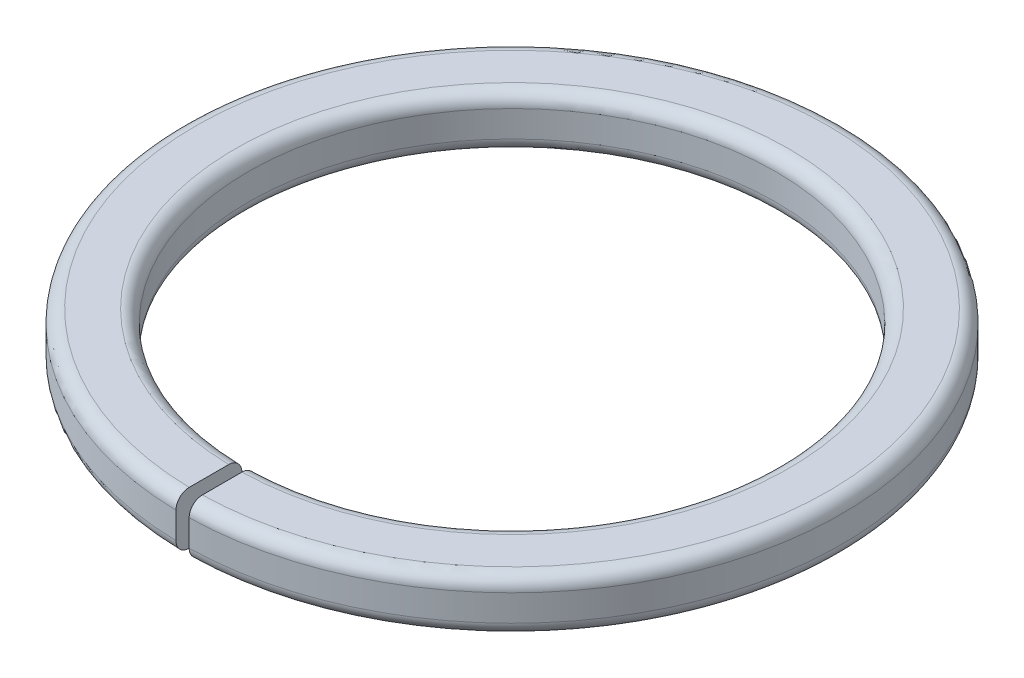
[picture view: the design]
ISO-10303-21;
HEADER;
FILE_DESCRIPTION(('STEP AP214'),'2;1');
FILE_NAME('part.step','',(''),(''),'','','');
FILE_SCHEMA(('AUTOMOTIVE_DESIGN { 1 0 10303 214 1 1 1 1 }'));
ENDSEC;
DATA;
#1=APPLICATION_CONTEXT('core data for automotive mechanical design processes');
#2=APPLICATION_PROTOCOL_DEFINITION('international standard','automotive_design',2000,#1);
#3=PRODUCT_CONTEXT('',#1,'mechanical');
#4=PRODUCT('Part','Part','',(#3));
#5=PRODUCT_RELATED_PRODUCT_CATEGORY('part','',(#4));
#6=PRODUCT_DEFINITION_FORMATION('','',#4);
#7=PRODUCT_DEFINITION_CONTEXT('part definition',#1,'design');
#8=PRODUCT_DEFINITION('design','',#6,#7);
#9=PRODUCT_DEFINITION_SHAPE('','',#8);
#10=(LENGTH_UNIT() NAMED_UNIT(*) SI_UNIT(.MILLI.,.METRE.));
#11=(NAMED_UNIT(*) PLANE_ANGLE_UNIT() SI_UNIT($,.RADIAN.));
#12=(NAMED_UNIT(*) SI_UNIT($,.STERADIAN.) SOLID_ANGLE_UNIT());
#13=UNCERTAINTY_MEASURE_WITH_UNIT(LENGTH_MEASURE(1.E-05),#10,'distance_accuracy_value','');
#14=(GEOMETRIC_REPRESENTATION_CONTEXT(3) GLOBAL_UNCERTAINTY_ASSIGNED_CONTEXT((#13)) GLOBAL_UNIT_ASSIGNED_CONTEXT((#10,
#11,#12)) REPRESENTATION_CONTEXT('',''));
#15=CARTESIAN_POINT('',(0.,0.,0.));
#16=DIRECTION('',(0.,0.,1.));
#17=DIRECTION('',(1.,0.,0.));
#18=AXIS2_PLACEMENT_3D('',#15,#16,#17);
#19=CARTESIAN_POINT('',(0.,0.8,0.));
#20=DIRECTION('',(0.,1.,0.));
#21=DIRECTION('',(0.,0.,1.));
#22=AXIS2_PLACEMENT_3D('',#19,#20,#21);
#23=PLANE('',#22);
#24=DIRECTION('',(0.,0.,1.));
#25=VECTOR('',#24,1.);
#26=CARTESIAN_POINT('',(-0.1,0.8,0.));
#27=LINE('',#26,#25);
#28=CARTESIAN_POINT('',(-0.1,0.8,4.1988093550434));
#29=VERTEX_POINT('',#28);
#30=CARTESIAN_POINT('',(-0.1,0.8,4.79895822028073));
#31=VERTEX_POINT('',#30);
#32=EDGE_CURVE('E48',#29,#31,#27,.T.);
#33=ORIENTED_EDGE('',*,*,#32,.F.);
#34=CARTESIAN_POINT('',(0.,0.8,0.));
#35=DIRECTION('',(0.,1.,0.));
#36=DIRECTION('',(0.,0.,1.));
#37=AXIS2_PLACEMENT_3D('',#34,#35,#36);
#38=CIRCLE('',#37,4.2);
#39=CARTESIAN_POINT('',(0.1,0.8,4.1988093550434));
#40=VERTEX_POINT('',#39);
#41=EDGE_CURVE('E110',#29,#40,#38,.F.);
#42=ORIENTED_EDGE('',*,*,#41,.T.);
#43=DIRECTION('',(0.,0.,-1.));
#44=VECTOR('',#43,1.);
#45=CARTESIAN_POINT('',(0.1,0.8,0.));
#46=LINE('',#45,#44);
#47=CARTESIAN_POINT('',(0.1,0.8,4.79895822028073));
#48=VERTEX_POINT('',#47);
#49=EDGE_CURVE('E113',#48,#40,#46,.T.);
#50=ORIENTED_EDGE('',*,*,#49,.F.);
#51=CARTESIAN_POINT('',(0.,0.8,0.));
#52=DIRECTION('',(0.,1.,0.));
#53=DIRECTION('',(0.,0.,1.));
#54=AXIS2_PLACEMENT_3D('',#51,#52,#53);
#55=CIRCLE('',#54,4.8);
#56=EDGE_CURVE('E112',#48,#31,#55,.T.);
#57=ORIENTED_EDGE('',*,*,#56,.T.);
#58=EDGE_LOOP('',(#33,#42,#50,#57));
#59=FACE_BOUND('',#58,.T.);
#60=ADVANCED_FACE('F30',(#59),#23,.T.);
#61=CARTESIAN_POINT('',(0.,0.,0.));
#62=DIRECTION('',(0.,1.,0.));
#63=DIRECTION('',(0.,0.,1.));
#64=AXIS2_PLACEMENT_3D('',#61,#62,#63);
#65=PLANE('',#64);
#66=CARTESIAN_POINT('',(0.,0.,0.));
#67=DIRECTION('',(0.,1.,0.));
#68=DIRECTION('',(0.,0.,1.));
#69=AXIS2_PLACEMENT_3D('',#66,#67,#68);
#70=CIRCLE('',#69,4.2);
#71=CARTESIAN_POINT('',(0.1,0.,4.1988093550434));
#72=VERTEX_POINT('',#71);
#73=CARTESIAN_POINT('',(-0.1,0.,4.1988093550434));
#74=VERTEX_POINT('',#73);
#75=EDGE_CURVE('E176',#72,#74,#70,.T.);
#76=ORIENTED_EDGE('',*,*,#75,.T.);
#77=DIRECTION('',(0.,0.,1.));
#78=VECTOR('',#77,1.);
#79=CARTESIAN_POINT('',(-0.1,0.,0.));
#80=LINE('',#79,#78);
#81=CARTESIAN_POINT('',(-0.1,-1.44818612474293E-11,4.79895822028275));
#82=VERTEX_POINT('',#81);
#83=EDGE_CURVE('E166',#74,#82,#80,.T.);
#84=ORIENTED_EDGE('',*,*,#83,.T.);
#85=CARTESIAN_POINT('',(0.,0.,0.));
#86=DIRECTION('',(0.,1.,0.));
#87=DIRECTION('',(0.,0.,1.));
#88=AXIS2_PLACEMENT_3D('',#85,#86,#87);
#89=CIRCLE('',#88,4.8);
#90=CARTESIAN_POINT('',(0.1,0.,4.79895822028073));
#91=VERTEX_POINT('',#90);
#92=EDGE_CURVE('E179',#82,#91,#89,.F.);
#93=ORIENTED_EDGE('',*,*,#92,.T.);
#94=DIRECTION('',(0.,0.,-1.));
#95=VECTOR('',#94,1.);
#96=CARTESIAN_POINT('',(0.1,0.,0.));
#97=LINE('',#96,#95);
#98=EDGE_CURVE('E150',#91,#72,#97,.T.);
#99=ORIENTED_EDGE('',*,*,#98,.T.);
#100=EDGE_LOOP('',(#76,#84,#93,#99));
#101=FACE_BOUND('',#100,.T.);
#102=ADVANCED_FACE('F194',(#101),#65,.F.);
#103=CARTESIAN_POINT('',(0.,0.8,0.));
#104=DIRECTION('',(0.,-1.,0.));
#105=DIRECTION('',(0.,0.,-1.));
#106=AXIS2_PLACEMENT_3D('',#103,#104,#105);
#107=CYLINDRICAL_SURFACE('',#106,5.);
#108=CARTESIAN_POINT('',(0.,0.2,0.));
#109=DIRECTION('',(0.,1.,0.));
#110=DIRECTION('',(0.,0.,1.));
#111=AXIS2_PLACEMENT_3D('',#108,#109,#110);
#112=CIRCLE('',#111,5.);
#113=CARTESIAN_POINT('',(0.1,0.2,4.99899989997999));
#114=VERTEX_POINT('',#113);
#115=CARTESIAN_POINT('',(-0.1,0.2,4.99899989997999));
#116=VERTEX_POINT('',#115);
#117=EDGE_CURVE('E173',#114,#116,#112,.T.);
#118=ORIENTED_EDGE('',*,*,#117,.T.);
#119=DIRECTION('',(0.,-1.,0.));
#120=VECTOR('',#119,1.);
#121=CARTESIAN_POINT('',(-0.1,0.8,4.99899989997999));
#122=LINE('',#121,#120);
#123=CARTESIAN_POINT('',(-0.1,0.6,4.99899989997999));
#124=VERTEX_POINT('',#123);
#125=EDGE_CURVE('E203',#116,#124,#122,.F.);
#126=ORIENTED_EDGE('',*,*,#125,.T.);
#127=CARTESIAN_POINT('',(0.,0.6,0.));
#128=DIRECTION('',(0.,1.,0.));
#129=DIRECTION('',(0.,0.,1.));
#130=AXIS2_PLACEMENT_3D('',#127,#128,#129);
#131=CIRCLE('',#130,5.);
#132=CARTESIAN_POINT('',(0.1,0.6,4.99899989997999));
#133=VERTEX_POINT('',#132);
#134=EDGE_CURVE('E104',#124,#133,#131,.F.);
#135=ORIENTED_EDGE('',*,*,#134,.T.);
#136=DIRECTION('',(0.,-1.,0.));
#137=VECTOR('',#136,1.);
#138=CARTESIAN_POINT('',(0.1,0.8,4.99899989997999));
#139=LINE('',#138,#137);
#140=EDGE_CURVE('E56',#133,#114,#139,.T.);
#141=ORIENTED_EDGE('',*,*,#140,.T.);
#142=EDGE_LOOP('',(#118,#126,#135,#141));
#143=FACE_BOUND('',#142,.T.);
#144=ADVANCED_FACE('F32',(#143),#107,.T.);
#145=CARTESIAN_POINT('',(0.,0.8,0.));
#146=DIRECTION('',(0.,-1.,0.));
#147=DIRECTION('',(0.,0.,-1.));
#148=AXIS2_PLACEMENT_3D('',#145,#146,#147);
#149=CYLINDRICAL_SURFACE('',#148,4.);
#150=DIRECTION('',(0.,-1.,0.));
#151=VECTOR('',#150,1.);
#152=CARTESIAN_POINT('',(-0.1,0.8,3.99874980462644));
#153=LINE('',#152,#151);
#154=CARTESIAN_POINT('',(-0.1,0.199999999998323,3.99874980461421));
#155=VERTEX_POINT('',#154);
#156=CARTESIAN_POINT('',(-0.1,0.6,3.99874980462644));
#157=VERTEX_POINT('',#156);
#158=EDGE_CURVE('E99',#155,#157,#153,.F.);
#159=ORIENTED_EDGE('',*,*,#158,.F.);
#160=CARTESIAN_POINT('',(0.,0.2,0.));
#161=DIRECTION('',(0.,1.,0.));
#162=DIRECTION('',(0.,0.,1.));
#163=AXIS2_PLACEMENT_3D('',#160,#161,#162);
#164=CIRCLE('',#163,4.);
#165=CARTESIAN_POINT('',(0.1,0.200000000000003,3.99874980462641));
#166=VERTEX_POINT('',#165);
#167=EDGE_CURVE('E119',#155,#166,#164,.F.);
#168=ORIENTED_EDGE('',*,*,#167,.T.);
#169=DIRECTION('',(0.,-1.,0.));
#170=VECTOR('',#169,1.);
#171=CARTESIAN_POINT('',(0.1,0.8,3.99874980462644));
#172=LINE('',#171,#170);
#173=CARTESIAN_POINT('',(0.1,0.6,3.99874980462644));
#174=VERTEX_POINT('',#173);
#175=EDGE_CURVE('E149',#174,#166,#172,.T.);
#176=ORIENTED_EDGE('',*,*,#175,.F.);
#177=CARTESIAN_POINT('',(0.,0.6,0.));
#178=DIRECTION('',(0.,1.,0.));
#179=DIRECTION('',(0.,0.,1.));
#180=AXIS2_PLACEMENT_3D('',#177,#178,#179);
#181=CIRCLE('',#180,4.);
#182=EDGE_CURVE('E182',#174,#157,#181,.T.);
#183=ORIENTED_EDGE('',*,*,#182,.T.);
#184=EDGE_LOOP('',(#159,#168,#176,#183));
#185=FACE_BOUND('',#184,.T.);
#186=ADVANCED_FACE('F187',(#185),#149,.F.);
#187=CARTESIAN_POINT('',(0.,0.2,0.));
#188=DIRECTION('',(0.,1.,0.));
#189=DIRECTION('',(0.,0.,1.));
#190=AXIS2_PLACEMENT_3D('',#187,#188,#189);
#191=TOROIDAL_SURFACE('',#190,4.8,0.2);
#192=CARTESIAN_POINT('',(-0.1,0.106676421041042,4.62202654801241));
#193=CARTESIAN_POINT('',(-0.1,0.116610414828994,4.61678496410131));
#194=CARTESIAN_POINT('',(-0.1,0.126994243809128,4.6123783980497));
#195=CARTESIAN_POINT('',(-0.1,0.148363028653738,4.60536767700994));
#196=CARTESIAN_POINT('',(-0.1,0.159348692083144,4.60276569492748));
#197=CARTESIAN_POINT('',(-0.1,0.181596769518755,4.59944448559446));
#198=CARTESIAN_POINT('',(-0.1,0.192859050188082,4.5987243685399));
#199=CARTESIAN_POINT('',(-0.1,0.215341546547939,4.59918555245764));
#200=CARTESIAN_POINT('',(-0.1,0.226561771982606,4.60036638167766));
#201=CARTESIAN_POINT('',(-0.1,0.248645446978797,4.60459490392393));
#202=CARTESIAN_POINT('',(-0.1,0.259508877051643,4.60764269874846));
#203=CARTESIAN_POINT('',(-0.1,0.280570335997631,4.61551882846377));
#204=CARTESIAN_POINT('',(-0.1,0.290768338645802,4.62034723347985));
#205=CARTESIAN_POINT('',(-0.1,0.310209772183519,4.63164771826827));
#206=CARTESIAN_POINT('',(-0.1,0.319453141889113,4.63811990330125));
#207=CARTESIAN_POINT('',(-0.1,0.336722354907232,4.65252394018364));
#208=CARTESIAN_POINT('',(-0.1,0.344748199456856,4.6604557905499));
#209=CARTESIAN_POINT('',(-0.1,0.359356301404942,4.677555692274));
#210=CARTESIAN_POINT('',(-0.1,0.365938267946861,4.68672399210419));
#211=CARTESIAN_POINT('',(-0.1,0.37746994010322,4.7060352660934));
#212=CARTESIAN_POINT('',(-0.1,0.382419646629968,4.71617823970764));
#213=CARTESIAN_POINT('',(-0.1,0.390547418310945,4.73715334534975));
#214=CARTESIAN_POINT('',(-0.1,0.393725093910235,4.7479856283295));
#215=CARTESIAN_POINT('',(-0.1,0.398217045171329,4.77002991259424));
#216=CARTESIAN_POINT('',(-0.1,0.3995313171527,4.78124191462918));
#217=CARTESIAN_POINT('',(-0.1,0.400259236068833,4.80372900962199));
#218=CARTESIAN_POINT('',(-0.1,0.399672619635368,4.81500411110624));
#219=CARTESIAN_POINT('',(-0.1,0.396614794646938,4.83729579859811));
#220=CARTESIAN_POINT('',(-0.1,0.394143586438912,4.84831238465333));
#221=CARTESIAN_POINT('',(-0.1,0.387386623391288,4.86977430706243));
#222=CARTESIAN_POINT('',(-0.1,0.383100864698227,4.88021964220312));
#223=CARTESIAN_POINT('',(-0.1,0.372836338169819,4.90024241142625));
#224=CARTESIAN_POINT('',(-0.1,0.366857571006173,4.90981984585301));
#225=CARTESIAN_POINT('',(-0.1,0.353377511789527,4.92783359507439));
#226=CARTESIAN_POINT('',(-0.1,0.34587641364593,4.93627005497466));
#227=CARTESIAN_POINT('',(-0.1,0.329564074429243,4.95176359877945));
#228=CARTESIAN_POINT('',(-0.1,0.320752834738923,4.9588206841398));
#229=CARTESIAN_POINT('',(-0.1,0.302072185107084,4.97135367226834));
#230=CARTESIAN_POINT('',(-0.1,0.29220298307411,4.97682988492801));
#231=CARTESIAN_POINT('',(-0.1,0.271685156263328,4.98604733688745));
#232=CARTESIAN_POINT('',(-0.1,0.261036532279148,4.98978857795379));
#233=CARTESIAN_POINT('',(-0.1,0.239264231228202,4.99542921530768));
#234=CARTESIAN_POINT('',(-0.1,0.228140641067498,4.99732894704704));
#235=CARTESIAN_POINT('',(-0.1,0.205732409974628,4.999233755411));
#236=CARTESIAN_POINT('',(-0.1,0.194447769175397,4.9992388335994));
#237=CARTESIAN_POINT('',(-0.1,0.172038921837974,4.99735428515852));
#238=CARTESIAN_POINT('',(-0.1,0.160914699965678,4.99546484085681));
#239=CARTESIAN_POINT('',(-0.1,0.139141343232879,4.98984521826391));
#240=CARTESIAN_POINT('',(-0.1,0.128492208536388,4.98611503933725));
#241=CARTESIAN_POINT('',(-0.1,0.107970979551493,4.97691981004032));
#242=CARTESIAN_POINT('',(-0.1,0.0980989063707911,4.97145471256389));
#243=CARTESIAN_POINT('',(-0.1,0.0794122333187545,4.95894493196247));
#244=CARTESIAN_POINT('',(-0.1,0.0705976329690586,4.95190024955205));
#245=CARTESIAN_POINT('',(-0.1,0.0542747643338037,4.93643026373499));
#246=CARTESIAN_POINT('',(-0.1,0.0467666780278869,4.92800476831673));
#247=CARTESIAN_POINT('',(-0.1,0.0332712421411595,4.91001306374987));
#248=CARTESIAN_POINT('',(-0.1,0.0272838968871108,4.90044685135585));
#249=CARTESIAN_POINT('',(-0.1,0.0169986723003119,4.88044327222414));
#250=CARTESIAN_POINT('',(-0.1,0.0127011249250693,4.87000573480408));
#251=CARTESIAN_POINT('',(-0.1,0.0059189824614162,4.84855736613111));
#252=CARTESIAN_POINT('',(-0.1,0.00343439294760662,4.83754653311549));
#253=CARTESIAN_POINT('',(-0.1,0.00034827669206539,4.81526186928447));
#254=CARTESIAN_POINT('',(-0.1,-0.000252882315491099,4.80398798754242));
#255=CARTESIAN_POINT('',(-0.1,0.000445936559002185,4.78149972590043));
#256=CARTESIAN_POINT('',(-0.1,0.0017458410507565,4.7702853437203));
#257=CARTESIAN_POINT('',(-0.1,0.00620964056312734,4.74823428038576));
#258=CARTESIAN_POINT('',(-0.1,0.00937348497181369,4.7373975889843));
#259=CARTESIAN_POINT('',(-0.1,0.0174767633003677,4.71640634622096));
#260=CARTESIAN_POINT('',(-0.1,0.022416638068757,4.7062519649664));
#261=CARTESIAN_POINT('',(-0.1,0.033932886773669,4.68691354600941));
#262=CARTESIAN_POINT('',(-0.1,0.0405099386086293,4.67772991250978));
#263=CARTESIAN_POINT('',(-0.1,0.0551084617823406,4.66060628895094));
#264=CARTESIAN_POINT('',(-0.1,0.0631281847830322,4.65266481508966));
#265=CARTESIAN_POINT('',(-0.1,0.0771400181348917,4.64095160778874));
#266=CARTESIAN_POINT('',(-0.1,0.0827649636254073,4.63673287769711));
#267=CARTESIAN_POINT('',(-0.1,0.0944267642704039,4.62890941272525));
#268=CARTESIAN_POINT('',(-0.1,0.100463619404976,4.62530467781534));
#269=CARTESIAN_POINT('',(-0.1,0.106676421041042,4.62202654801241));
#270=B_SPLINE_CURVE_WITH_KNOTS('',3,(#192,#193,#194,#195,#196,#197,#198,#199,#200,#201,#202,
#203,#204,#205,#206,#207,#208,#209,#210,#211,#212,#213,#214,#215,#216,#217,#218,#219,#220,#221,
#222,#223,#224,#225,#226,#227,#228,#229,#230,#231,#232,#233,#234,#235,#236,#237,#238,#239,#240,
#241,#242,#243,#244,#245,#246,#247,#248,#249,#250,#251,#252,#253,#254,#255,#256,#257,#258,#259,
#260,#261,#262,#263,#264,#265,#266,#267,#268,#269),.UNSPECIFIED.,.T.,.F.,(4,2,2,2,2,2,2,2,2,2,2,
2,2,2,2,2,2,2,2,2,2,2,2,2,2,2,2,2,2,2,2,2,2,2,2,2,2,2,4),(0.,0.0336704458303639,
0.0673813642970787,0.101076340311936,0.13476295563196,0.168451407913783,0.202141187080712,
0.235833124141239,0.269525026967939,0.30322371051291,0.336922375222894,0.370628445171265,
0.404334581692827,0.438045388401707,0.471756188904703,0.505467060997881,0.539177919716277,
0.572884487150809,0.606591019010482,0.640290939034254,0.673990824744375,0.707684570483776,
0.741378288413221,0.775068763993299,0.808759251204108,0.842450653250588,0.876142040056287,
0.909838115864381,0.943534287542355,0.977237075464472,1.01093996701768,1.04464943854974,
1.07835760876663,1.11206486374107,1.14578049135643,1.17951010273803,1.21319911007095,
1.23425688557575,1.25531466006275),.UNSPECIFIED.);
#271=EDGE_CURVE('E205',#116,#82,#270,.T.);
#272=ORIENTED_EDGE('',*,*,#271,.F.);
#273=ORIENTED_EDGE('',*,*,#117,.F.);
#274=CARTESIAN_POINT('',(0.1,0.106676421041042,4.62202654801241));
#275=CARTESIAN_POINT('',(0.1,0.0967401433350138,4.62727046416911));
#276=CARTESIAN_POINT('',(0.1,0.0872395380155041,4.63335746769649));
#277=CARTESIAN_POINT('',(0.1,0.0693874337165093,4.64704547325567));
#278=CARTESIAN_POINT('',(0.1,0.0610373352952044,4.65464829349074));
#279=CARTESIAN_POINT('',(0.1,0.0457356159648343,4.67114505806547));
#280=CARTESIAN_POINT('',(0.1,0.0387833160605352,4.68003837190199));
#281=CARTESIAN_POINT('',(0.1,0.0264721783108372,4.69886340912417));
#282=CARTESIAN_POINT('',(0.1,0.021112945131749,4.70879487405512));
#283=CARTESIAN_POINT('',(0.1,0.0121359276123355,4.72941913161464));
#284=CARTESIAN_POINT('',(0.1,0.00851860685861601,4.74011212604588));
#285=CARTESIAN_POINT('',(0.1,0.00313007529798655,4.76195400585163));
#286=CARTESIAN_POINT('',(0.1,0.00135893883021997,4.77310290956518));
#287=CARTESIAN_POINT('',(0.1,-0.000286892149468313,4.79554134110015));
#288=CARTESIAN_POINT('',(0.1,-0.000161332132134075,4.80683088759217));
#289=CARTESIAN_POINT('',(0.1,0.00198331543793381,4.82922865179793));
#290=CARTESIAN_POINT('',(0.1,0.00400239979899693,4.84033686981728));
#291=CARTESIAN_POINT('',(0.1,0.00987692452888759,4.8620568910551));
#292=CARTESIAN_POINT('',(0.1,0.0137324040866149,4.87266868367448));
#293=CARTESIAN_POINT('',(0.1,0.0231703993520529,4.89309424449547));
#294=CARTESIAN_POINT('',(0.1,0.0287529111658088,4.90290801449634));
#295=CARTESIAN_POINT('',(0.1,0.0414858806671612,4.92145773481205));
#296=CARTESIAN_POINT('',(0.1,0.0486361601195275,4.9301938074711));
#297=CARTESIAN_POINT('',(0.1,0.0643021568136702,4.94634124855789));
#298=CARTESIAN_POINT('',(0.1,0.072817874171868,4.95375261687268));
#299=CARTESIAN_POINT('',(0.1,0.090971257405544,4.96703872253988));
#300=CARTESIAN_POINT('',(0.1,0.100608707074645,4.97291375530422));
#301=CARTESIAN_POINT('',(0.1,0.120733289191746,4.98296208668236));
#302=CARTESIAN_POINT('',(0.1,0.13122042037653,4.98713538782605));
#303=CARTESIAN_POINT('',(0.1,0.152744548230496,4.9936610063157));
#304=CARTESIAN_POINT('',(0.1,0.163781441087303,4.99601366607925));
#305=CARTESIAN_POINT('',(0.1,0.186093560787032,4.99883243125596));
#306=CARTESIAN_POINT('',(0.1,0.197368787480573,4.99929853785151));
#307=CARTESIAN_POINT('',(0.1,0.219836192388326,4.99833100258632));
#308=CARTESIAN_POINT('',(0.1,0.231028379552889,4.99689756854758));
#309=CARTESIAN_POINT('',(0.1,0.253013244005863,4.99217205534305));
#310=CARTESIAN_POINT('',(0.1,0.26380592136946,4.98887997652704));
#311=CARTESIAN_POINT('',(0.1,0.284685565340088,4.98053067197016));
#312=CARTESIAN_POINT('',(0.1,0.294772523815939,4.97547342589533));
#313=CARTESIAN_POINT('',(0.1,0.313954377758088,4.96373746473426));
#314=CARTESIAN_POINT('',(0.1,0.323049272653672,4.95705874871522));
#315=CARTESIAN_POINT('',(0.1,0.33999010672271,4.9422685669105));
#316=CARTESIAN_POINT('',(0.1,0.347835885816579,4.9341569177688));
#317=CARTESIAN_POINT('',(0.1,0.362054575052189,4.9167317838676));
#318=CARTESIAN_POINT('',(0.1,0.368427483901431,4.90741829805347));
#319=CARTESIAN_POINT('',(0.1,0.379520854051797,4.88785193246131));
#320=CARTESIAN_POINT('',(0.1,0.384240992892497,4.8775988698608));
#321=CARTESIAN_POINT('',(0.1,0.391893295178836,4.8564459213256));
#322=CARTESIAN_POINT('',(0.1,0.394825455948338,4.84554603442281));
#323=CARTESIAN_POINT('',(0.1,0.398819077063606,4.82340670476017));
#324=CARTESIAN_POINT('',(0.1,0.399880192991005,4.8121671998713));
#325=CARTESIAN_POINT('',(0.1,0.400100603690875,4.78966956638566));
#326=CARTESIAN_POINT('',(0.1,0.399259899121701,4.77841143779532));
#327=CARTESIAN_POINT('',(0.1,0.395700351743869,4.75619503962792));
#328=CARTESIAN_POINT('',(0.1,0.392981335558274,4.74523679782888));
#329=CARTESIAN_POINT('',(0.1,0.385742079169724,4.72393234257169));
#330=CARTESIAN_POINT('',(0.1,0.381221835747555,4.71358613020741));
#331=CARTESIAN_POINT('',(0.1,0.370508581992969,4.69380002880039));
#332=CARTESIAN_POINT('',(0.1,0.364315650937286,4.68436009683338));
#333=CARTESIAN_POINT('',(0.1,0.350432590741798,4.66665413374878));
#334=CARTESIAN_POINT('',(0.1,0.34274245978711,4.65838810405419));
#335=CARTESIAN_POINT('',(0.1,0.326084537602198,4.64326603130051));
#336=CARTESIAN_POINT('',(0.1,0.317116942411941,4.63640977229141));
#337=CARTESIAN_POINT('',(0.1,0.298158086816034,4.62430078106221));
#338=CARTESIAN_POINT('',(0.1,0.288166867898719,4.61904798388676));
#339=CARTESIAN_POINT('',(0.1,0.267447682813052,4.61029631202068));
#340=CARTESIAN_POINT('',(0.1,0.256719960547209,4.60679685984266));
#341=CARTESIAN_POINT('',(0.1,0.23482624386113,4.60164825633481));
#342=CARTESIAN_POINT('',(0.1,0.223660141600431,4.59999956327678));
#343=CARTESIAN_POINT('',(0.1,0.201207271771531,4.59860018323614));
#344=CARTESIAN_POINT('',(0.1,0.189920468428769,4.59885007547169));
#345=CARTESIAN_POINT('',(0.1,0.167558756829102,4.60124273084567));
#346=CARTESIAN_POINT('',(0.1,0.156483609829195,4.6033832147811));
#347=CARTESIAN_POINT('',(0.1,0.138922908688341,4.60833990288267));
#348=CARTESIAN_POINT('',(0.1,0.132275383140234,4.61060067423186));
#349=CARTESIAN_POINT('',(0.1,0.119254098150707,4.61580692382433));
#350=CARTESIAN_POINT('',(0.1,0.112880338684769,4.6187524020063));
#351=CARTESIAN_POINT('',(0.1,0.106676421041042,4.62202654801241));
#352=B_SPLINE_CURVE_WITH_KNOTS('',3,(#274,#275,#276,#277,#278,#279,#280,#281,#282,#283,#284,
#285,#286,#287,#288,#289,#290,#291,#292,#293,#294,#295,#296,#297,#298,#299,#300,#301,#302,#303,
#304,#305,#306,#307,#308,#309,#310,#311,#312,#313,#314,#315,#316,#317,#318,#319,#320,#321,#322,
#323,#324,#325,#326,#327,#328,#329,#330,#331,#332,#333,#334,#335,#336,#337,#338,#339,#340,#341,
#342,#343,#344,#345,#346,#347,#348,#349,#350,#351),.UNSPECIFIED.,.T.,.F.,(4,2,2,2,2,2,2,2,2,2,2,
2,2,2,2,2,2,2,2,2,2,2,2,2,2,2,2,2,2,2,2,2,2,2,2,2,2,2,4),(0.,0.0336797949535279,
0.0674002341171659,0.101104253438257,0.134799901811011,0.168504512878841,0.202210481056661,
0.235920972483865,0.26963140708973,0.303342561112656,0.337053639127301,0.370760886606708,
0.404468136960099,0.438168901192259,0.471869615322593,0.505563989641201,0.539258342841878,
0.57294900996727,0.60663967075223,0.640330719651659,0.674021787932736,0.707717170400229,
0.741412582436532,0.775114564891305,0.80881659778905,0.842524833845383,0.876233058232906,
0.909944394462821,0.943655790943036,0.977365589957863,1.01107542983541,1.04478010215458,
1.07848340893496,1.11217560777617,1.14587614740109,1.17958696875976,1.21325720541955,
1.23428587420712,1.25531454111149),.UNSPECIFIED.);
#353=EDGE_CURVE('E137',#91,#114,#352,.T.);
#354=ORIENTED_EDGE('',*,*,#353,.F.);
#355=ORIENTED_EDGE('',*,*,#92,.F.);
#356=EDGE_LOOP('',(#272,#273,#354,#355));
#357=FACE_BOUND('',#356,.T.);
#358=ADVANCED_FACE('F154',(#357),#191,.T.);
#359=CARTESIAN_POINT('',(0.,0.2,0.));
#360=DIRECTION('',(0.,1.,0.));
#361=DIRECTION('',(0.,0.,1.));
#362=AXIS2_PLACEMENT_3D('',#359,#360,#361);
#363=TOROIDAL_SURFACE('',#362,4.2,0.2);
#364=CARTESIAN_POINT('',(-0.1,0.108972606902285,4.0206723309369));
#365=CARTESIAN_POINT('',(-0.1,0.118972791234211,4.01555973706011));
#366=CARTESIAN_POINT('',(-0.1,0.129411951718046,4.01128782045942));
#367=CARTESIAN_POINT('',(-0.1,0.150868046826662,4.00455388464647));
#368=CARTESIAN_POINT('',(-0.1,0.161885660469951,4.00209404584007));
#369=CARTESIAN_POINT('',(-0.1,0.18417331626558,3.9990604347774));
#370=CARTESIAN_POINT('',(-0.1,0.195443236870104,3.99848577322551));
#371=CARTESIAN_POINT('',(-0.1,0.217916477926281,3.99923707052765));
#372=CARTESIAN_POINT('',(-0.1,0.229119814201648,4.00056255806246));
#373=CARTESIAN_POINT('',(-0.1,0.251145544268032,4.00507549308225));
#374=CARTESIAN_POINT('',(-0.1,0.261967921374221,4.00826302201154));
#375=CARTESIAN_POINT('',(-0.1,0.282924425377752,4.01640968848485));
#376=CARTESIAN_POINT('',(-0.1,0.293058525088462,4.02136889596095));
#377=CARTESIAN_POINT('',(-0.1,0.312351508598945,4.03291850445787));
#378=CARTESIAN_POINT('',(-0.1,0.321510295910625,4.03950906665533));
#379=CARTESIAN_POINT('',(-0.1,0.338591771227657,4.05413388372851));
#380=CARTESIAN_POINT('',(-0.1,0.346514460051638,4.06216813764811));
#381=CARTESIAN_POINT('',(-0.1,0.360901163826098,4.07945457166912));
#382=CARTESIAN_POINT('',(-0.1,0.36736478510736,4.0887070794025));
#383=CARTESIAN_POINT('',(-0.1,0.37864743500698,4.10816565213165));
#384=CARTESIAN_POINT('',(-0.1,0.383466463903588,4.11837171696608));
#385=CARTESIAN_POINT('',(-0.1,0.391324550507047,4.13945084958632));
#386=CARTESIAN_POINT('',(-0.1,0.39436309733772,4.15032410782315));
#387=CARTESIAN_POINT('',(-0.1,0.398571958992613,4.17242640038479));
#388=CARTESIAN_POINT('',(-0.1,0.399742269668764,4.18365543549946));
#389=CARTESIAN_POINT('',(-0.1,0.400181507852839,4.20615259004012));
#390=CARTESIAN_POINT('',(-0.1,0.39945010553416,4.2174207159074));
#391=CARTESIAN_POINT('',(-0.1,0.396105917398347,4.23967424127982));
#392=CARTESIAN_POINT('',(-0.1,0.393493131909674,4.25065964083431));
#393=CARTESIAN_POINT('',(-0.1,0.386460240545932,4.27203573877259));
#394=CARTESIAN_POINT('',(-0.1,0.382040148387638,4.28242644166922));
#395=CARTESIAN_POINT('',(-0.1,0.37151795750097,4.30231811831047));
#396=CARTESIAN_POINT('',(-0.1,0.365415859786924,4.31181909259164));
#397=CARTESIAN_POINT('',(-0.1,0.351703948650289,4.32965979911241));
#398=CARTESIAN_POINT('',(-0.1,0.344094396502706,4.33799973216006));
#399=CARTESIAN_POINT('',(-0.1,0.327582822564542,4.35328328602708));
#400=CARTESIAN_POINT('',(-0.1,0.318680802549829,4.36022690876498));
#401=CARTESIAN_POINT('',(-0.1,0.299839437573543,4.37251883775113));
#402=CARTESIAN_POINT('',(-0.1,0.28990035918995,4.37786755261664));
#403=CARTESIAN_POINT('',(-0.1,0.26926514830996,4.38681998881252));
#404=CARTESIAN_POINT('',(-0.1,0.258569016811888,4.39042371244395));
#405=CARTESIAN_POINT('',(-0.1,0.236726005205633,4.39578305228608));
#406=CARTESIAN_POINT('',(-0.1,0.225579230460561,4.3975390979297));
#407=CARTESIAN_POINT('',(-0.1,0.203149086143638,4.39915463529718));
#408=CARTESIAN_POINT('',(-0.1,0.191865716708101,4.39901412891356));
#409=CARTESIAN_POINT('',(-0.1,0.169484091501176,4.3968406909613));
#410=CARTESIAN_POINT('',(-0.1,0.158385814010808,4.39480798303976));
#411=CARTESIAN_POINT('',(-0.1,0.136688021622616,4.3889082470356));
#412=CARTESIAN_POINT('',(-0.1,0.126088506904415,4.38504121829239));
#413=CARTESIAN_POINT('',(-0.1,0.105688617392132,4.37558254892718));
#414=CARTESIAN_POINT('',(-0.1,0.0958882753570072,4.36999083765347));
#415=CARTESIAN_POINT('',(-0.1,0.0773652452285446,4.35724173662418));
#416=CARTESIAN_POINT('',(-0.1,0.0686425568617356,4.35008434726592));
#417=CARTESIAN_POINT('',(-0.1,0.0525206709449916,4.33440570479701));
#418=CARTESIAN_POINT('',(-0.1,0.0451217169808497,4.32588420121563));
#419=CARTESIAN_POINT('',(-0.1,0.0318590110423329,4.30772022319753));
#420=CARTESIAN_POINT('',(-0.1,0.0259952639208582,4.29807774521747));
#421=CARTESIAN_POINT('',(-0.1,0.0159678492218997,4.27794291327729));
#422=CARTESIAN_POINT('',(-0.1,0.0118046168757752,4.26745034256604));
#423=CARTESIAN_POINT('',(-0.1,0.00529833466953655,4.24591525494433));
#424=CARTESIAN_POINT('',(-0.1,0.00295529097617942,4.23487273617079));
#425=CARTESIAN_POINT('',(-0.1,0.000155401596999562,4.21254833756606));
#426=CARTESIAN_POINT('',(-0.1,-0.000300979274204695,4.2012663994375));
#427=CARTESIAN_POINT('',(-0.1,0.000686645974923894,4.17878643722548));
#428=CARTESIAN_POINT('',(-0.1,0.00213057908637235,4.16758840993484));
#429=CARTESIAN_POINT('',(-0.1,0.00687766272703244,4.1455937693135));
#430=CARTESIAN_POINT('',(-0.1,0.0101808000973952,4.1347971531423));
#431=CARTESIAN_POINT('',(-0.1,0.0185540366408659,4.11390891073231));
#432=CARTESIAN_POINT('',(-0.1,0.0236245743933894,4.10381746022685));
#433=CARTESIAN_POINT('',(-0.1,0.0353897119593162,4.0846262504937));
#434=CARTESIAN_POINT('',(-0.1,0.0420849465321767,4.07552688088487));
#435=CARTESIAN_POINT('',(-0.1,0.0569039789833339,4.05859046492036));
#436=CARTESIAN_POINT('',(-0.1,0.065026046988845,4.05075191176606));
#437=CARTESIAN_POINT('',(-0.1,0.0791893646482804,4.03921839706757));
#438=CARTESIAN_POINT('',(-0.1,0.0848691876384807,4.03507169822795));
#439=CARTESIAN_POINT('',(-0.1,0.0966329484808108,4.02739778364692));
#440=CARTESIAN_POINT('',(-0.1,0.102716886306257,4.02387056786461));
#441=CARTESIAN_POINT('',(-0.1,0.108972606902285,4.0206723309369));
#442=B_SPLINE_CURVE_WITH_KNOTS('',3,(#364,#365,#366,#367,#368,#369,#370,#371,#372,#373,#374,
#375,#376,#377,#378,#379,#380,#381,#382,#383,#384,#385,#386,#387,#388,#389,#390,#391,#392,#393,
#394,#395,#396,#397,#398,#399,#400,#401,#402,#403,#404,#405,#406,#407,#408,#409,#410,#411,#412,
#413,#414,#415,#416,#417,#418,#419,#420,#421,#422,#423,#424,#425,#426,#427,#428,#429,#430,#431,
#432,#433,#434,#435,#436,#437,#438,#439,#440,#441),.UNSPECIFIED.,.T.,.F.,(4,2,2,2,2,2,2,2,2,2,2,
2,2,2,2,2,2,2,2,2,2,2,2,2,2,2,2,2,2,2,2,2,2,2,2,2,2,2,4),(0.,0.0336682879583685,
0.0673770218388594,0.101069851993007,0.134754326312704,0.168440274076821,0.202127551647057,
0.235818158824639,0.269508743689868,0.303208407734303,0.336908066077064,0.37061738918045,
0.404326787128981,0.438042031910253,0.471757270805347,0.505472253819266,0.539187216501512,
0.572896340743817,0.606605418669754,0.640305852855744,0.674006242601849,0.707698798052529,
0.74139131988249,0.775079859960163,0.80876841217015,0.842458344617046,0.876148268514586,
0.909844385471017,0.94354060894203,0.977245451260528,1.01095040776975,1.04466366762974,
1.078375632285,1.11208735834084,1.14580745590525,1.1795407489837,1.21323342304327,
1.23429497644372,1.25535652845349),.UNSPECIFIED.);
#443=EDGE_CURVE('E161',#74,#155,#442,.T.);
#444=ORIENTED_EDGE('',*,*,#443,.F.);
#445=ORIENTED_EDGE('',*,*,#75,.F.);
#446=CARTESIAN_POINT('',(0.1,0.108972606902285,4.0206723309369));
#447=CARTESIAN_POINT('',(0.1,0.0989692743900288,4.02578765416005));
#448=CARTESIAN_POINT('',(0.1,0.0893907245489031,4.03175168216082));
#449=CARTESIAN_POINT('',(0.1,0.0713631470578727,4.04520849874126));
#450=CARTESIAN_POINT('',(0.1,0.062915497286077,4.05270312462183));
#451=CARTESIAN_POINT('',(0.1,0.047401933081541,4.06900141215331));
#452=CARTESIAN_POINT('',(0.1,0.040335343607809,4.07780443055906));
#453=CARTESIAN_POINT('',(0.1,0.0277820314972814,4.09646931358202));
#454=CARTESIAN_POINT('',(0.1,0.0222949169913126,4.10633091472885));
#455=CARTESIAN_POINT('',(0.1,0.0130517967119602,4.12683835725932));
#456=CARTESIAN_POINT('',(0.1,0.00929634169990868,4.13748444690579));
#457=CARTESIAN_POINT('',(0.1,0.00362551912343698,4.1592563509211));
#458=CARTESIAN_POINT('',(0.1,0.00171022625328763,4.17038218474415));
#459=CARTESIAN_POINT('',(0.1,-0.000225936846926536,4.19279957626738));
#460=CARTESIAN_POINT('',(0.1,-0.000246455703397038,4.2040911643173));
#461=CARTESIAN_POINT('',(0.1,0.00160842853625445,4.22651751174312));
#462=CARTESIAN_POINT('',(0.1,0.00348382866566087,4.23765227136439));
#463=CARTESIAN_POINT('',(0.1,0.00907750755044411,4.25944923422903));
#464=CARTESIAN_POINT('',(0.1,0.0127958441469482,4.27011142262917));
#465=CARTESIAN_POINT('',(0.1,0.0219700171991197,4.29066005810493));
#466=CARTESIAN_POINT('',(0.1,0.0274258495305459,4.30054650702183));
#467=CARTESIAN_POINT('',(0.1,0.0399193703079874,4.31926145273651));
#468=CARTESIAN_POINT('',(0.1,0.0469568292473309,4.3280901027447));
#469=CARTESIAN_POINT('',(0.1,0.0624144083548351,4.34444024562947));
#470=CARTESIAN_POINT('',(0.1,0.070834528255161,4.35196173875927));
#471=CARTESIAN_POINT('',(0.1,0.088816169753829,4.36548203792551));
#472=CARTESIAN_POINT('',(0.1,0.0983774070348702,4.37148122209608));
#473=CARTESIAN_POINT('',(0.1,0.118371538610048,4.38178878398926));
#474=CARTESIAN_POINT('',(0.1,0.128804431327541,4.3860971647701));
#475=CARTESIAN_POINT('',(0.1,0.150242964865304,4.39289975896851));
#476=CARTESIAN_POINT('',(0.1,0.161248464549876,4.39539441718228));
#477=CARTESIAN_POINT('',(0.1,0.183522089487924,4.39850035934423));
#478=CARTESIAN_POINT('',(0.1,0.194790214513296,4.39911164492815));
#479=CARTESIAN_POINT('',(0.1,0.217267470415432,4.39843351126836));
#480=CARTESIAN_POINT('',(0.1,0.228476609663,4.39714436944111));
#481=CARTESIAN_POINT('',(0.1,0.2505193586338,4.39270253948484));
#482=CARTESIAN_POINT('',(0.1,0.261352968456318,4.38954985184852));
#483=CARTESIAN_POINT('',(0.1,0.282337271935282,4.38147050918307));
#484=CARTESIAN_POINT('',(0.1,0.292487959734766,4.37654383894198));
#485=CARTESIAN_POINT('',(0.1,0.31181832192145,4.36505653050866));
#486=CARTESIAN_POINT('',(0.1,0.320997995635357,4.35849589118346));
#487=CARTESIAN_POINT('',(0.1,0.338127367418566,4.3439258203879));
#488=CARTESIAN_POINT('',(0.1,0.346076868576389,4.33591615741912));
#489=CARTESIAN_POINT('',(0.1,0.360518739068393,4.3186762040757));
#490=CARTESIAN_POINT('',(0.1,0.367011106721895,4.30944591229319));
#491=CARTESIAN_POINT('',(0.1,0.378356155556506,4.29002425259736));
#492=CARTESIAN_POINT('',(0.1,0.383208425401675,4.27983264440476));
#493=CARTESIAN_POINT('',(0.1,0.391133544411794,4.25877958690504));
#494=CARTESIAN_POINT('',(0.1,0.394206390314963,4.2479181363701));
#495=CARTESIAN_POINT('',(0.1,0.398486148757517,4.22583089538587));
#496=CARTESIAN_POINT('',(0.1,0.399692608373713,4.21460501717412));
#497=CARTESIAN_POINT('',(0.1,0.400204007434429,4.19211003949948));
#498=CARTESIAN_POINT('',(0.1,0.399508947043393,4.18084094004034));
#499=CARTESIAN_POINT('',(0.1,0.396236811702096,4.1585778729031));
#500=CARTESIAN_POINT('',(0.1,0.393659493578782,4.14758394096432));
#501=CARTESIAN_POINT('',(0.1,0.386695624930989,4.12618482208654));
#502=CARTESIAN_POINT('',(0.1,0.382309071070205,4.11577963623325));
#503=CARTESIAN_POINT('',(0.1,0.37185137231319,4.09585403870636));
#504=CARTESIAN_POINT('',(0.1,0.365780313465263,4.08633358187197));
#505=CARTESIAN_POINT('',(0.1,0.352125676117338,4.0684473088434));
#506=CARTESIAN_POINT('',(0.1,0.344542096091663,4.06008149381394));
#507=CARTESIAN_POINT('',(0.1,0.328079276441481,4.04474387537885));
#508=CARTESIAN_POINT('',(0.1,0.31920029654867,4.0377717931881));
#509=CARTESIAN_POINT('',(0.1,0.30039789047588,4.02541804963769));
#510=CARTESIAN_POINT('',(0.1,0.29047450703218,4.02003632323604));
#511=CARTESIAN_POINT('',(0.1,0.269869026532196,4.01101779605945));
#512=CARTESIAN_POINT('',(0.1,0.259187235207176,4.00738029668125));
#513=CARTESIAN_POINT('',(0.1,0.237361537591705,4.00194993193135));
#514=CARTESIAN_POINT('',(0.1,0.22621751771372,4.00015752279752));
#515=CARTESIAN_POINT('',(0.1,0.203785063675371,3.99846921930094));
#516=CARTESIAN_POINT('',(0.1,0.192496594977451,3.99857378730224));
#517=CARTESIAN_POINT('',(0.1,0.170107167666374,4.00067830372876));
#518=CARTESIAN_POINT('',(0.1,0.159005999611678,4.0026759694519));
#519=CARTESIAN_POINT('',(0.1,0.141385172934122,4.00740567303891));
#520=CARTESIAN_POINT('',(0.1,0.13471067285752,4.00958013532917));
#521=CARTESIAN_POINT('',(0.1,0.121626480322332,4.01461694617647));
#522=CARTESIAN_POINT('',(0.1,0.115216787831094,4.01747929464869));
#523=CARTESIAN_POINT('',(0.1,0.108972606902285,4.0206723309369));
#524=B_SPLINE_CURVE_WITH_KNOTS('',3,(#446,#447,#448,#449,#450,#451,#452,#453,#454,#455,#456,
#457,#458,#459,#460,#461,#462,#463,#464,#465,#466,#467,#468,#469,#470,#471,#472,#473,#474,#475,
#476,#477,#478,#479,#480,#481,#482,#483,#484,#485,#486,#487,#488,#489,#490,#491,#492,#493,#494,
#495,#496,#497,#498,#499,#500,#501,#502,#503,#504,#505,#506,#507,#508,#509,#510,#511,#512,#513,
#514,#515,#516,#517,#518,#519,#520,#521,#522,#523),.UNSPECIFIED.,.T.,.F.,(4,2,2,2,2,2,2,2,2,2,2,
2,2,2,2,2,2,2,2,2,2,2,2,2,2,2,2,2,2,2,2,2,2,2,2,2,2,2,4),(0.,0.0336804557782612,
0.0674015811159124,0.101106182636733,0.134802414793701,0.168509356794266,0.202217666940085,
0.235932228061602,0.269646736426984,0.303362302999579,0.337077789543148,0.370788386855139,
0.404498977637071,0.438201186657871,0.471903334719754,0.505597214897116,0.539291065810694,
0.572979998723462,0.606668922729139,0.640358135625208,0.674047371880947,0.707741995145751,
0.741436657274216,0.775139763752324,0.808842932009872,0.842554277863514,0.876265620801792,
0.909981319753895,0.943697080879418,0.977411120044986,1.01112519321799,1.04483251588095,
1.07853845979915,1.11223089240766,1.14593165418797,1.17964063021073,1.21330901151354,
1.23433269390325,1.25535637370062),.UNSPECIFIED.);
#525=EDGE_CURVE('E144',#166,#72,#524,.T.);
#526=ORIENTED_EDGE('',*,*,#525,.F.);
#527=ORIENTED_EDGE('',*,*,#167,.F.);
#528=EDGE_LOOP('',(#444,#445,#526,#527));
#529=FACE_BOUND('',#528,.T.);
#530=ADVANCED_FACE('F151',(#529),#363,.T.);
#531=CARTESIAN_POINT('',(0.,0.6,0.));
#532=DIRECTION('',(0.,1.,0.));
#533=DIRECTION('',(0.,0.,1.));
#534=AXIS2_PLACEMENT_3D('',#531,#532,#533);
#535=TOROIDAL_SURFACE('',#534,4.2,0.2);
#536=CARTESIAN_POINT('',(-0.1,0.691027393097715,4.0206723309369));
#537=CARTESIAN_POINT('',(-0.1,0.701030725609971,4.02578765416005));
#538=CARTESIAN_POINT('',(-0.1,0.710609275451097,4.03175168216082));
#539=CARTESIAN_POINT('',(-0.1,0.728636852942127,4.04520849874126));
#540=CARTESIAN_POINT('',(-0.1,0.737084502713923,4.05270312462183));
#541=CARTESIAN_POINT('',(-0.1,0.752598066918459,4.06900141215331));
#542=CARTESIAN_POINT('',(-0.1,0.759664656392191,4.07780443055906));
#543=CARTESIAN_POINT('',(-0.1,0.772217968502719,4.09646931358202));
#544=CARTESIAN_POINT('',(-0.1,0.777705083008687,4.10633091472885));
#545=CARTESIAN_POINT('',(-0.1,0.78694820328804,4.12683835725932));
#546=CARTESIAN_POINT('',(-0.1,0.790703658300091,4.13748444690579));
#547=CARTESIAN_POINT('',(-0.1,0.796374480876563,4.1592563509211));
#548=CARTESIAN_POINT('',(-0.1,0.798289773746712,4.17038218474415));
#549=CARTESIAN_POINT('',(-0.1,0.800225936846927,4.19279957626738));
#550=CARTESIAN_POINT('',(-0.1,0.800246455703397,4.2040911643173));
#551=CARTESIAN_POINT('',(-0.1,0.798391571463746,4.22651751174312));
#552=CARTESIAN_POINT('',(-0.1,0.796516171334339,4.23765227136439));
#553=CARTESIAN_POINT('',(-0.1,0.790922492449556,4.25944923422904));
#554=CARTESIAN_POINT('',(-0.1,0.787204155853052,4.27011142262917));
#555=CARTESIAN_POINT('',(-0.1,0.77802998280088,4.29066005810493));
#556=CARTESIAN_POINT('',(-0.1,0.772574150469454,4.30054650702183));
#557=CARTESIAN_POINT('',(-0.1,0.760080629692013,4.31926145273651));
#558=CARTESIAN_POINT('',(-0.1,0.753043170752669,4.3280901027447));
#559=CARTESIAN_POINT('',(-0.1,0.737585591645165,4.34444024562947));
#560=CARTESIAN_POINT('',(-0.1,0.729165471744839,4.35196173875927));
#561=CARTESIAN_POINT('',(-0.1,0.711183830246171,4.36548203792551));
#562=CARTESIAN_POINT('',(-0.1,0.70162259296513,4.37148122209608));
#563=CARTESIAN_POINT('',(-0.1,0.681628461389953,4.38178878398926));
#564=CARTESIAN_POINT('',(-0.1,0.671195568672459,4.3860971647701));
#565=CARTESIAN_POINT('',(-0.1,0.649757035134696,4.39289975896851));
#566=CARTESIAN_POINT('',(-0.1,0.638751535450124,4.39539441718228));
#567=CARTESIAN_POINT('',(-0.1,0.616477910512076,4.39850035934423));
#568=CARTESIAN_POINT('',(-0.1,0.605209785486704,4.39911164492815));
#569=CARTESIAN_POINT('',(-0.1,0.582732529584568,4.39843351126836));
#570=CARTESIAN_POINT('',(-0.1,0.571523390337,4.39714436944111));
#571=CARTESIAN_POINT('',(-0.1,0.5494806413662,4.39270253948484));
#572=CARTESIAN_POINT('',(-0.1,0.538647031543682,4.38954985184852));
#573=CARTESIAN_POINT('',(-0.1,0.517662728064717,4.38147050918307));
#574=CARTESIAN_POINT('',(-0.1,0.507512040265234,4.37654383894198));
#575=CARTESIAN_POINT('',(-0.1,0.48818167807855,4.36505653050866));
#576=CARTESIAN_POINT('',(-0.1,0.479002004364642,4.35849589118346));
#577=CARTESIAN_POINT('',(-0.1,0.461872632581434,4.3439258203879));
#578=CARTESIAN_POINT('',(-0.1,0.45392313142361,4.33591615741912));
#579=CARTESIAN_POINT('',(-0.1,0.439481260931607,4.3186762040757));
#580=CARTESIAN_POINT('',(-0.1,0.432988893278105,4.30944591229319));
#581=CARTESIAN_POINT('',(-0.1,0.421643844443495,4.29002425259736));
#582=CARTESIAN_POINT('',(-0.1,0.416791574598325,4.27983264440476));
#583=CARTESIAN_POINT('',(-0.1,0.408866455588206,4.25877958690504));
#584=CARTESIAN_POINT('',(-0.1,0.405793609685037,4.2479181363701));
#585=CARTESIAN_POINT('',(-0.1,0.401513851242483,4.22583089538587));
#586=CARTESIAN_POINT('',(-0.1,0.400307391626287,4.21460501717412));
#587=CARTESIAN_POINT('',(-0.1,0.399795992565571,4.19211003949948));
#588=CARTESIAN_POINT('',(-0.1,0.400491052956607,4.18084094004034));
#589=CARTESIAN_POINT('',(-0.1,0.403763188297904,4.1585778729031));
#590=CARTESIAN_POINT('',(-0.1,0.406340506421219,4.14758394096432));
#591=CARTESIAN_POINT('',(-0.1,0.413304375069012,4.12618482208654));
#592=CARTESIAN_POINT('',(-0.1,0.417690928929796,4.11577963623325));
#593=CARTESIAN_POINT('',(-0.1,0.42814862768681,4.09585403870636));
#594=CARTESIAN_POINT('',(-0.1,0.434219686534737,4.08633358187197));
#595=CARTESIAN_POINT('',(-0.1,0.447874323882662,4.0684473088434));
#596=CARTESIAN_POINT('',(-0.1,0.455457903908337,4.06008149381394));
#597=CARTESIAN_POINT('',(-0.1,0.471920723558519,4.04474387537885));
#598=CARTESIAN_POINT('',(-0.1,0.48079970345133,4.0377717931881));
#599=CARTESIAN_POINT('',(-0.1,0.49960210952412,4.02541804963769));
#600=CARTESIAN_POINT('',(-0.1,0.50952549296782,4.02003632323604));
#601=CARTESIAN_POINT('',(-0.1,0.530130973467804,4.01101779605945));
#602=CARTESIAN_POINT('',(-0.1,0.540812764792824,4.00738029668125));
#603=CARTESIAN_POINT('',(-0.1,0.562638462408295,4.00194993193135));
#604=CARTESIAN_POINT('',(-0.1,0.57378248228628,4.00015752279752));
#605=CARTESIAN_POINT('',(-0.1,0.596214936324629,3.99846921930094));
#606=CARTESIAN_POINT('',(-0.1,0.607503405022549,3.99857378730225));
#607=CARTESIAN_POINT('',(-0.1,0.629892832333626,4.00067830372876));
#608=CARTESIAN_POINT('',(-0.1,0.640994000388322,4.0026759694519));
#609=CARTESIAN_POINT('',(-0.1,0.658614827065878,4.00740567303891));
#610=CARTESIAN_POINT('',(-0.1,0.66528932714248,4.00958013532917));
#611=CARTESIAN_POINT('',(-0.1,0.678373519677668,4.01461694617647));
#612=CARTESIAN_POINT('',(-0.1,0.684783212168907,4.01747929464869));
#613=CARTESIAN_POINT('',(-0.1,0.691027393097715,4.0206723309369));
#614=B_SPLINE_CURVE_WITH_KNOTS('',3,(#536,#537,#538,#539,#540,#541,#542,#543,#544,#545,#546,
#547,#548,#549,#550,#551,#552,#553,#554,#555,#556,#557,#558,#559,#560,#561,#562,#563,#564,#565,
#566,#567,#568,#569,#570,#571,#572,#573,#574,#575,#576,#577,#578,#579,#580,#581,#582,#583,#584,
#585,#586,#587,#588,#589,#590,#591,#592,#593,#594,#595,#596,#597,#598,#599,#600,#601,#602,#603,
#604,#605,#606,#607,#608,#609,#610,#611,#612,#613),.UNSPECIFIED.,.T.,.F.,(4,2,2,2,2,2,2,2,2,2,2,
2,2,2,2,2,2,2,2,2,2,2,2,2,2,2,2,2,2,2,2,2,2,2,2,2,2,2,4),(0.,0.0336804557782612,
0.0674015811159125,0.101106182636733,0.134802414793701,0.168509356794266,0.202217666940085,
0.235932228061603,0.269646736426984,0.303362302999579,0.337077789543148,0.370788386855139,
0.404498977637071,0.438201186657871,0.471903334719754,0.505597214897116,0.539291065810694,
0.572979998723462,0.606668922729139,0.640358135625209,0.674047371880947,0.707741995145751,
0.741436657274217,0.775139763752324,0.808842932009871,0.842554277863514,0.876265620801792,
0.909981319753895,0.943697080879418,0.977411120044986,1.01112519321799,1.04483251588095,
1.07853845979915,1.11223089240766,1.14593165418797,1.17964063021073,1.21330901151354,
1.23433269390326,1.25535637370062),.UNSPECIFIED.);
#615=EDGE_CURVE('E96',#157,#29,#614,.T.);
#616=ORIENTED_EDGE('',*,*,#615,.F.);
#617=ORIENTED_EDGE('',*,*,#182,.F.);
#618=CARTESIAN_POINT('',(0.1,0.691027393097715,4.0206723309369));
#619=CARTESIAN_POINT('',(0.1,0.68102720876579,4.01555973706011));
#620=CARTESIAN_POINT('',(0.1,0.670588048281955,4.01128782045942));
#621=CARTESIAN_POINT('',(0.1,0.649131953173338,4.00455388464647));
#622=CARTESIAN_POINT('',(0.1,0.638114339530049,4.00209404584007));
#623=CARTESIAN_POINT('',(0.1,0.61582668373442,3.9990604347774));
#624=CARTESIAN_POINT('',(0.1,0.604556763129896,3.99848577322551));
#625=CARTESIAN_POINT('',(0.1,0.582083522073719,3.99923707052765));
#626=CARTESIAN_POINT('',(0.1,0.570880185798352,4.00056255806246));
#627=CARTESIAN_POINT('',(0.1,0.548854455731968,4.00507549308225));
#628=CARTESIAN_POINT('',(0.1,0.538032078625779,4.00826302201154));
#629=CARTESIAN_POINT('',(0.1,0.517075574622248,4.01640968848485));
#630=CARTESIAN_POINT('',(0.1,0.506941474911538,4.02136889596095));
#631=CARTESIAN_POINT('',(0.1,0.487648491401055,4.03291850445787));
#632=CARTESIAN_POINT('',(0.1,0.478489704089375,4.03950906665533));
#633=CARTESIAN_POINT('',(0.1,0.461408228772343,4.05413388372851));
#634=CARTESIAN_POINT('',(0.1,0.453485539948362,4.06216813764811));
#635=CARTESIAN_POINT('',(0.1,0.439098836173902,4.07945457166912));
#636=CARTESIAN_POINT('',(0.1,0.43263521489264,4.0887070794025));
#637=CARTESIAN_POINT('',(0.1,0.42135256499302,4.10816565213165));
#638=CARTESIAN_POINT('',(0.1,0.416533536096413,4.11837171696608));
#639=CARTESIAN_POINT('',(0.1,0.408675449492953,4.13945084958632));
#640=CARTESIAN_POINT('',(0.1,0.40563690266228,4.15032410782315));
#641=CARTESIAN_POINT('',(0.1,0.401428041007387,4.17242640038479));
#642=CARTESIAN_POINT('',(0.1,0.400257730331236,4.18365543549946));
#643=CARTESIAN_POINT('',(0.1,0.399818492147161,4.20615259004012));
#644=CARTESIAN_POINT('',(0.1,0.40054989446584,4.2174207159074));
#645=CARTESIAN_POINT('',(0.1,0.403894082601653,4.23967424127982));
#646=CARTESIAN_POINT('',(0.1,0.406506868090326,4.25065964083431));
#647=CARTESIAN_POINT('',(0.1,0.413539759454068,4.27203573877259));
#648=CARTESIAN_POINT('',(0.1,0.417959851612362,4.28242644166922));
#649=CARTESIAN_POINT('',(0.1,0.42848204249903,4.30231811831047));
#650=CARTESIAN_POINT('',(0.1,0.434584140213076,4.31181909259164));
#651=CARTESIAN_POINT('',(0.1,0.448296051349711,4.32965979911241));
#652=CARTESIAN_POINT('',(0.1,0.455905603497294,4.33799973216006));
#653=CARTESIAN_POINT('',(0.1,0.472417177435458,4.35328328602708));
#654=CARTESIAN_POINT('',(0.1,0.481319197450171,4.36022690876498));
#655=CARTESIAN_POINT('',(0.1,0.500160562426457,4.37251883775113));
#656=CARTESIAN_POINT('',(0.1,0.51009964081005,4.37786755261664));
#657=CARTESIAN_POINT('',(0.1,0.53073485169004,4.38681998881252));
#658=CARTESIAN_POINT('',(0.1,0.541430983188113,4.39042371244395));
#659=CARTESIAN_POINT('',(0.1,0.563273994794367,4.39578305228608));
#660=CARTESIAN_POINT('',(0.1,0.574420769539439,4.3975390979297));
#661=CARTESIAN_POINT('',(0.1,0.596850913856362,4.39915463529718));
#662=CARTESIAN_POINT('',(0.1,0.608134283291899,4.39901412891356));
#663=CARTESIAN_POINT('',(0.1,0.630515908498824,4.3968406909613));
#664=CARTESIAN_POINT('',(0.1,0.641614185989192,4.39480798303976));
#665=CARTESIAN_POINT('',(0.1,0.663311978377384,4.3889082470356));
#666=CARTESIAN_POINT('',(0.1,0.673911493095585,4.38504121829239));
#667=CARTESIAN_POINT('',(0.1,0.694311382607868,4.37558254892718));
#668=CARTESIAN_POINT('',(0.1,0.704111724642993,4.36999083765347));
#669=CARTESIAN_POINT('',(0.1,0.722634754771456,4.35724173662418));
#670=CARTESIAN_POINT('',(0.1,0.731357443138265,4.35008434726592));
#671=CARTESIAN_POINT('',(0.1,0.747479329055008,4.33440570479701));
#672=CARTESIAN_POINT('',(0.1,0.75487828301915,4.32588420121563));
#673=CARTESIAN_POINT('',(0.1,0.768140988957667,4.30772022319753));
#674=CARTESIAN_POINT('',(0.1,0.774004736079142,4.29807774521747));
#675=CARTESIAN_POINT('',(0.1,0.7840321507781,4.27794291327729));
#676=CARTESIAN_POINT('',(0.1,0.788195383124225,4.26745034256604));
#677=CARTESIAN_POINT('',(0.1,0.794701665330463,4.24591525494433));
#678=CARTESIAN_POINT('',(0.1,0.797044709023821,4.23487273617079));
#679=CARTESIAN_POINT('',(0.1,0.799844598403,4.21254833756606));
#680=CARTESIAN_POINT('',(0.1,0.800300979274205,4.2012663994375));
#681=CARTESIAN_POINT('',(0.1,0.799313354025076,4.17878643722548));
#682=CARTESIAN_POINT('',(0.1,0.797869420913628,4.16758840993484));
#683=CARTESIAN_POINT('',(0.1,0.793122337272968,4.1455937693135));
#684=CARTESIAN_POINT('',(0.1,0.789819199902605,4.1347971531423));
#685=CARTESIAN_POINT('',(0.1,0.781445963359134,4.11390891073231));
#686=CARTESIAN_POINT('',(0.1,0.77637542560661,4.10381746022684));
#687=CARTESIAN_POINT('',(0.1,0.764610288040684,4.0846262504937));
#688=CARTESIAN_POINT('',(0.1,0.757915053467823,4.07552688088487));
#689=CARTESIAN_POINT('',(0.1,0.743096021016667,4.05859046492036));
#690=CARTESIAN_POINT('',(0.1,0.734973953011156,4.05075191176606));
#691=CARTESIAN_POINT('',(0.1,0.720810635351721,4.03921839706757));
#692=CARTESIAN_POINT('',(0.1,0.71513081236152,4.03507169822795));
#693=CARTESIAN_POINT('',(0.1,0.703367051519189,4.02739778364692));
#694=CARTESIAN_POINT('',(0.1,0.697283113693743,4.02387056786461));
#695=CARTESIAN_POINT('',(0.1,0.691027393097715,4.0206723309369));
#696=B_SPLINE_CURVE_WITH_KNOTS('',3,(#618,#619,#620,#621,#622,#623,#624,#625,#626,#627,#628,
#629,#630,#631,#632,#633,#634,#635,#636,#637,#638,#639,#640,#641,#642,#643,#644,#645,#646,#647,
#648,#649,#650,#651,#652,#653,#654,#655,#656,#657,#658,#659,#660,#661,#662,#663,#664,#665,#666,
#667,#668,#669,#670,#671,#672,#673,#674,#675,#676,#677,#678,#679,#680,#681,#682,#683,#684,#685,
#686,#687,#688,#689,#690,#691,#692,#693,#694,#695),.UNSPECIFIED.,.T.,.F.,(4,2,2,2,2,2,2,2,2,2,2,
2,2,2,2,2,2,2,2,2,2,2,2,2,2,2,2,2,2,2,2,2,2,2,2,2,2,2,4),(0.,0.0336682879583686,
0.0673770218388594,0.101069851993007,0.134754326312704,0.168440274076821,0.202127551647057,
0.235818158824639,0.269508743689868,0.303208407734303,0.336908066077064,0.37061738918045,
0.404326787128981,0.438042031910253,0.471757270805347,0.505472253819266,0.539187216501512,
0.572896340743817,0.606605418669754,0.640305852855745,0.674006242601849,0.70769879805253,
0.74139131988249,0.775079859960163,0.80876841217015,0.842458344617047,0.876148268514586,
0.909844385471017,0.94354060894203,0.977245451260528,1.01095040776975,1.04466366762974,
1.078375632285,1.11208735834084,1.14580745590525,1.1795407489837,1.21323342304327,
1.23429497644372,1.25535652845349),.UNSPECIFIED.);
#697=EDGE_CURVE('E117',#40,#174,#696,.T.);
#698=ORIENTED_EDGE('',*,*,#697,.F.);
#699=ORIENTED_EDGE('',*,*,#41,.F.);
#700=EDGE_LOOP('',(#616,#617,#698,#699));
#701=FACE_BOUND('',#700,.T.);
#702=ADVANCED_FACE('F116',(#701),#535,.T.);
#703=CARTESIAN_POINT('',(0.,0.6,0.));
#704=DIRECTION('',(0.,1.,0.));
#705=DIRECTION('',(0.,0.,1.));
#706=AXIS2_PLACEMENT_3D('',#703,#704,#705);
#707=TOROIDAL_SURFACE('',#706,4.8,0.2);
#708=CARTESIAN_POINT('',(-0.1,0.693323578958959,4.62202654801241));
#709=CARTESIAN_POINT('',(-0.1,0.703259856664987,4.62727046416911));
#710=CARTESIAN_POINT('',(-0.1,0.712760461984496,4.63335746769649));
#711=CARTESIAN_POINT('',(-0.1,0.730612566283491,4.64704547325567));
#712=CARTESIAN_POINT('',(-0.1,0.738962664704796,4.65464829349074));
#713=CARTESIAN_POINT('',(-0.1,0.754264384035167,4.67114505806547));
#714=CARTESIAN_POINT('',(-0.1,0.761216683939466,4.68003837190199));
#715=CARTESIAN_POINT('',(-0.1,0.773527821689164,4.69886340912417));
#716=CARTESIAN_POINT('',(-0.1,0.778887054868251,4.70879487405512));
#717=CARTESIAN_POINT('',(-0.1,0.787864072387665,4.72941913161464));
#718=CARTESIAN_POINT('',(-0.1,0.791481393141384,4.74011212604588));
#719=CARTESIAN_POINT('',(-0.1,0.796869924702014,4.76195400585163));
#720=CARTESIAN_POINT('',(-0.1,0.79864106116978,4.77310290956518));
#721=CARTESIAN_POINT('',(-0.1,0.800286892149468,4.79554134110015));
#722=CARTESIAN_POINT('',(-0.1,0.800161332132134,4.80683088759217));
#723=CARTESIAN_POINT('',(-0.1,0.798016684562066,4.82922865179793));
#724=CARTESIAN_POINT('',(-0.1,0.795997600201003,4.84033686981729));
#725=CARTESIAN_POINT('',(-0.1,0.790123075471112,4.8620568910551));
#726=CARTESIAN_POINT('',(-0.1,0.786267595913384,4.87266868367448));
#727=CARTESIAN_POINT('',(-0.1,0.776829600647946,4.89309424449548));
#728=CARTESIAN_POINT('',(-0.1,0.77124708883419,4.90290801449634));
#729=CARTESIAN_POINT('',(-0.1,0.758514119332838,4.92145773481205));
#730=CARTESIAN_POINT('',(-0.1,0.751363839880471,4.9301938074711));
#731=CARTESIAN_POINT('',(-0.1,0.735697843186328,4.94634124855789));
#732=CARTESIAN_POINT('',(-0.1,0.727182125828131,4.95375261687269));
#733=CARTESIAN_POINT('',(-0.1,0.709028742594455,4.96703872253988));
#734=CARTESIAN_POINT('',(-0.1,0.699391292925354,4.97291375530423));
#735=CARTESIAN_POINT('',(-0.1,0.679266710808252,4.98296208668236));
#736=CARTESIAN_POINT('',(-0.1,0.668779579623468,4.98713538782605));
#737=CARTESIAN_POINT('',(-0.1,0.647255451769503,4.9936610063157));
#738=CARTESIAN_POINT('',(-0.1,0.636218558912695,4.99601366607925));
#739=CARTESIAN_POINT('',(-0.1,0.613906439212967,4.99883243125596));
#740=CARTESIAN_POINT('',(-0.1,0.602631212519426,4.99929853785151));
#741=CARTESIAN_POINT('',(-0.1,0.580163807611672,4.99833100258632));
#742=CARTESIAN_POINT('',(-0.1,0.56897162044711,4.99689756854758));
#743=CARTESIAN_POINT('',(-0.1,0.546986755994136,4.99217205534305));
#744=CARTESIAN_POINT('',(-0.1,0.536194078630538,4.98887997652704));
#745=CARTESIAN_POINT('',(-0.1,0.515314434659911,4.98053067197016));
#746=CARTESIAN_POINT('',(-0.1,0.50522747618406,4.97547342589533));
#747=CARTESIAN_POINT('',(-0.1,0.486045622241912,4.96373746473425));
#748=CARTESIAN_POINT('',(-0.1,0.476950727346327,4.95705874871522));
#749=CARTESIAN_POINT('',(-0.1,0.46000989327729,4.9422685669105));
#750=CARTESIAN_POINT('',(-0.1,0.45216411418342,4.9341569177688));
#751=CARTESIAN_POINT('',(-0.1,0.437945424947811,4.9167317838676));
#752=CARTESIAN_POINT('',(-0.1,0.431572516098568,4.90741829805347));
#753=CARTESIAN_POINT('',(-0.1,0.420479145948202,4.88785193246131));
#754=CARTESIAN_POINT('',(-0.1,0.415759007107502,4.87759886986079));
#755=CARTESIAN_POINT('',(-0.1,0.408106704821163,4.85644592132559));
#756=CARTESIAN_POINT('',(-0.1,0.405174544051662,4.8455460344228));
#757=CARTESIAN_POINT('',(-0.1,0.401180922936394,4.82340670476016));
#758=CARTESIAN_POINT('',(-0.1,0.400119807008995,4.8121671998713));
#759=CARTESIAN_POINT('',(-0.1,0.399899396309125,4.78966956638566));
#760=CARTESIAN_POINT('',(-0.1,0.400740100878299,4.77841143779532));
#761=CARTESIAN_POINT('',(-0.1,0.404299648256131,4.75619503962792));
#762=CARTESIAN_POINT('',(-0.1,0.407018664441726,4.74523679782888));
#763=CARTESIAN_POINT('',(-0.1,0.414257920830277,4.72393234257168));
#764=CARTESIAN_POINT('',(-0.1,0.418778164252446,4.71358613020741));
#765=CARTESIAN_POINT('',(-0.1,0.429491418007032,4.69380002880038));
#766=CARTESIAN_POINT('',(-0.1,0.435684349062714,4.68436009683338));
#767=CARTESIAN_POINT('',(-0.1,0.449567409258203,4.66665413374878));
#768=CARTESIAN_POINT('',(-0.1,0.457257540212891,4.65838810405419));
#769=CARTESIAN_POINT('',(-0.1,0.473915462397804,4.64326603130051));
#770=CARTESIAN_POINT('',(-0.1,0.482883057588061,4.63640977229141));
#771=CARTESIAN_POINT('',(-0.1,0.501841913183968,4.62430078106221));
#772=CARTESIAN_POINT('',(-0.1,0.511833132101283,4.61904798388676));
#773=CARTESIAN_POINT('',(-0.1,0.532552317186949,4.61029631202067));
#774=CARTESIAN_POINT('',(-0.1,0.543280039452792,4.60679685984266));
#775=CARTESIAN_POINT('',(-0.1,0.565173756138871,4.60164825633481));
#776=CARTESIAN_POINT('',(-0.1,0.576339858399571,4.59999956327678));
#777=CARTESIAN_POINT('',(-0.1,0.598792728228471,4.59860018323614));
#778=CARTESIAN_POINT('',(-0.1,0.610079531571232,4.59885007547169));
#779=CARTESIAN_POINT('',(-0.1,0.632441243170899,4.60124273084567));
#780=CARTESIAN_POINT('',(-0.1,0.643516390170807,4.6033832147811));
#781=CARTESIAN_POINT('',(-0.1,0.66107709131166,4.60833990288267));
#782=CARTESIAN_POINT('',(-0.1,0.667724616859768,4.61060067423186));
#783=CARTESIAN_POINT('',(-0.1,0.680745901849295,4.61580692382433));
#784=CARTESIAN_POINT('',(-0.1,0.687119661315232,4.6187524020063));
#785=CARTESIAN_POINT('',(-0.1,0.693323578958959,4.62202654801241));
#786=B_SPLINE_CURVE_WITH_KNOTS('',3,(#708,#709,#710,#711,#712,#713,#714,#715,#716,#717,#718,
#719,#720,#721,#722,#723,#724,#725,#726,#727,#728,#729,#730,#731,#732,#733,#734,#735,#736,#737,
#738,#739,#740,#741,#742,#743,#744,#745,#746,#747,#748,#749,#750,#751,#752,#753,#754,#755,#756,
#757,#758,#759,#760,#761,#762,#763,#764,#765,#766,#767,#768,#769,#770,#771,#772,#773,#774,#775,
#776,#777,#778,#779,#780,#781,#782,#783,#784,#785),.UNSPECIFIED.,.T.,.F.,(4,2,2,2,2,2,2,2,2,2,2,
2,2,2,2,2,2,2,2,2,2,2,2,2,2,2,2,2,2,2,2,2,2,2,2,2,2,2,4),(0.,0.0336797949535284,
0.0674002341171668,0.101104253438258,0.134799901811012,0.168504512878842,0.202210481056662,
0.235920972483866,0.269631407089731,0.303342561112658,0.337053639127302,0.370760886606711,
0.4044681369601,0.438168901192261,0.471869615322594,0.505563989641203,0.53925834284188,
0.572949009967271,0.606639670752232,0.64033071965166,0.674021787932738,0.70771717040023,
0.741412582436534,0.775114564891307,0.808816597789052,0.842524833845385,0.876233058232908,
0.909944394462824,0.943655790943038,0.977365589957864,1.01107542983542,1.04478010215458,
1.07848340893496,1.11217560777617,1.1458761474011,1.17958696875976,1.21325720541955,
1.23428587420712,1.25531454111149),.UNSPECIFIED.);
#787=EDGE_CURVE('E11',#31,#124,#786,.T.);
#788=ORIENTED_EDGE('',*,*,#787,.F.);
#789=ORIENTED_EDGE('',*,*,#56,.F.);
#790=CARTESIAN_POINT('',(0.1,0.693323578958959,4.62202654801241));
#791=CARTESIAN_POINT('',(0.1,0.683389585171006,4.61678496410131));
#792=CARTESIAN_POINT('',(0.1,0.673005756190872,4.6123783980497));
#793=CARTESIAN_POINT('',(0.1,0.651636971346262,4.60536767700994));
#794=CARTESIAN_POINT('',(0.1,0.640651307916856,4.60276569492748));
#795=CARTESIAN_POINT('',(0.1,0.618403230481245,4.59944448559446));
#796=CARTESIAN_POINT('',(0.1,0.607140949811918,4.5987243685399));
#797=CARTESIAN_POINT('',(0.1,0.584658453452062,4.59918555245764));
#798=CARTESIAN_POINT('',(0.1,0.573438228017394,4.60036638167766));
#799=CARTESIAN_POINT('',(0.1,0.551354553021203,4.60459490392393));
#800=CARTESIAN_POINT('',(0.1,0.540491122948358,4.60764269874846));
#801=CARTESIAN_POINT('',(0.1,0.51942966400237,4.61551882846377));
#802=CARTESIAN_POINT('',(0.1,0.509231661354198,4.62034723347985));
#803=CARTESIAN_POINT('',(0.1,0.489790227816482,4.63164771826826));
#804=CARTESIAN_POINT('',(0.1,0.480546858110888,4.63811990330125));
#805=CARTESIAN_POINT('',(0.1,0.463277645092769,4.65252394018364));
#806=CARTESIAN_POINT('',(0.1,0.455251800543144,4.6604557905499));
#807=CARTESIAN_POINT('',(0.1,0.440643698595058,4.677555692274));
#808=CARTESIAN_POINT('',(0.1,0.43406173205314,4.68672399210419));
#809=CARTESIAN_POINT('',(0.1,0.42253005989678,4.7060352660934));
#810=CARTESIAN_POINT('',(0.1,0.417580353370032,4.71617823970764));
#811=CARTESIAN_POINT('',(0.1,0.409452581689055,4.73715334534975));
#812=CARTESIAN_POINT('',(0.1,0.406274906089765,4.7479856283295));
#813=CARTESIAN_POINT('',(0.1,0.401782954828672,4.77002991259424));
#814=CARTESIAN_POINT('',(0.1,0.4004686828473,4.78124191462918));
#815=CARTESIAN_POINT('',(0.1,0.399740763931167,4.80372900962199));
#816=CARTESIAN_POINT('',(0.1,0.400327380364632,4.81500411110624));
#817=CARTESIAN_POINT('',(0.1,0.403385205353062,4.83729579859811));
#818=CARTESIAN_POINT('',(0.1,0.405856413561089,4.84831238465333));
#819=CARTESIAN_POINT('',(0.1,0.412613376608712,4.86977430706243));
#820=CARTESIAN_POINT('',(0.1,0.416899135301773,4.88021964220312));
#821=CARTESIAN_POINT('',(0.1,0.427163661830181,4.90024241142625));
#822=CARTESIAN_POINT('',(0.1,0.433142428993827,4.90981984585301));
#823=CARTESIAN_POINT('',(0.1,0.446622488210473,4.92783359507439));
#824=CARTESIAN_POINT('',(0.1,0.45412358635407,4.93627005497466));
#825=CARTESIAN_POINT('',(0.1,0.470435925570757,4.95176359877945));
#826=CARTESIAN_POINT('',(0.1,0.479247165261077,4.9588206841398));
#827=CARTESIAN_POINT('',(0.1,0.497927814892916,4.97135367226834));
#828=CARTESIAN_POINT('',(0.1,0.50779701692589,4.97682988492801));
#829=CARTESIAN_POINT('',(0.1,0.528314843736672,4.98604733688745));
#830=CARTESIAN_POINT('',(0.1,0.538963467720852,4.98978857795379));
#831=CARTESIAN_POINT('',(0.1,0.560735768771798,4.99542921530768));
#832=CARTESIAN_POINT('',(0.1,0.571859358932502,4.99732894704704));
#833=CARTESIAN_POINT('',(0.1,0.594267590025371,4.999233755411));
#834=CARTESIAN_POINT('',(0.1,0.605552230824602,4.9992388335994));
#835=CARTESIAN_POINT('',(0.1,0.627961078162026,4.99735428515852));
#836=CARTESIAN_POINT('',(0.1,0.639085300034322,4.99546484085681));
#837=CARTESIAN_POINT('',(0.1,0.660858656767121,4.98984521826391));
#838=CARTESIAN_POINT('',(0.1,0.671507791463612,4.98611503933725));
#839=CARTESIAN_POINT('',(0.1,0.692029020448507,4.97691981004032));
#840=CARTESIAN_POINT('',(0.1,0.701901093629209,4.97145471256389));
#841=CARTESIAN_POINT('',(0.1,0.720587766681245,4.95894493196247));
#842=CARTESIAN_POINT('',(0.1,0.729402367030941,4.95190024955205));
#843=CARTESIAN_POINT('',(0.1,0.745725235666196,4.93643026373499));
#844=CARTESIAN_POINT('',(0.1,0.753233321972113,4.92800476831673));
#845=CARTESIAN_POINT('',(0.1,0.766728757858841,4.91001306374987));
#846=CARTESIAN_POINT('',(0.1,0.772716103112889,4.90044685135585));
#847=CARTESIAN_POINT('',(0.1,0.783001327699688,4.88044327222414));
#848=CARTESIAN_POINT('',(0.1,0.78729887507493,4.87000573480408));
#849=CARTESIAN_POINT('',(0.1,0.794081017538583,4.84855736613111));
#850=CARTESIAN_POINT('',(0.1,0.796565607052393,4.83754653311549));
#851=CARTESIAN_POINT('',(0.1,0.799651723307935,4.81526186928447));
#852=CARTESIAN_POINT('',(0.1,0.800252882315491,4.80398798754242));
#853=CARTESIAN_POINT('',(0.1,0.799554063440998,4.78149972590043));
#854=CARTESIAN_POINT('',(0.1,0.798254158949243,4.7702853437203));
#855=CARTESIAN_POINT('',(0.1,0.793790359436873,4.74823428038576));
#856=CARTESIAN_POINT('',(0.1,0.790626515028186,4.7373975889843));
#857=CARTESIAN_POINT('',(0.1,0.782523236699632,4.71640634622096));
#858=CARTESIAN_POINT('',(0.1,0.777583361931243,4.7062519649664));
#859=CARTESIAN_POINT('',(0.1,0.766067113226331,4.68691354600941));
#860=CARTESIAN_POINT('',(0.1,0.759490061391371,4.67772991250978));
#861=CARTESIAN_POINT('',(0.1,0.74489153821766,4.66060628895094));
#862=CARTESIAN_POINT('',(0.1,0.736871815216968,4.65266481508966));
#863=CARTESIAN_POINT('',(0.1,0.722859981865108,4.64095160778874));
#864=CARTESIAN_POINT('',(0.1,0.717235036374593,4.63673287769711));
#865=CARTESIAN_POINT('',(0.1,0.705573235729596,4.62890941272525));
#866=CARTESIAN_POINT('',(0.1,0.699536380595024,4.62530467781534));
#867=CARTESIAN_POINT('',(0.1,0.693323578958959,4.62202654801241));
#868=B_SPLINE_CURVE_WITH_KNOTS('',3,(#790,#791,#792,#793,#794,#795,#796,#797,#798,#799,#800,
#801,#802,#803,#804,#805,#806,#807,#808,#809,#810,#811,#812,#813,#814,#815,#816,#817,#818,#819,
#820,#821,#822,#823,#824,#825,#826,#827,#828,#829,#830,#831,#832,#833,#834,#835,#836,#837,#838,
#839,#840,#841,#842,#843,#844,#845,#846,#847,#848,#849,#850,#851,#852,#853,#854,#855,#856,#857,
#858,#859,#860,#861,#862,#863,#864,#865,#866,#867),.UNSPECIFIED.,.T.,.F.,(4,2,2,2,2,2,2,2,2,2,2,
2,2,2,2,2,2,2,2,2,2,2,2,2,2,2,2,2,2,2,2,2,2,2,2,2,2,2,4),(0.,0.033670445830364,
0.0673813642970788,0.101076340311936,0.13476295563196,0.168451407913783,0.202141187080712,
0.235833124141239,0.26952502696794,0.303223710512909,0.336922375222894,0.370628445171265,
0.404334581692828,0.438045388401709,0.471756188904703,0.505467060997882,0.539177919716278,
0.57288448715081,0.606591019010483,0.640290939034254,0.673990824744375,0.707684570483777,
0.741378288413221,0.7750687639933,0.808759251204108,0.842450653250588,0.876142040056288,
0.909838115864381,0.943534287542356,0.977237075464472,1.01093996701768,1.04464943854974,
1.07835760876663,1.11206486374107,1.14578049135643,1.17951010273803,1.21319911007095,
1.23425688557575,1.25531466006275),.UNSPECIFIED.);
#869=EDGE_CURVE('E42',#133,#48,#868,.T.);
#870=ORIENTED_EDGE('',*,*,#869,.F.);
#871=ORIENTED_EDGE('',*,*,#134,.F.);
#872=EDGE_LOOP('',(#788,#789,#870,#871));
#873=FACE_BOUND('',#872,.T.);
#874=ADVANCED_FACE('F125',(#873),#707,.T.);
#875=CARTESIAN_POINT('',(0.1,-9.2,0.));
#876=DIRECTION('',(1.,0.,0.));
#877=DIRECTION('',(0.,0.,-1.));
#878=AXIS2_PLACEMENT_3D('',#875,#876,#877);
#879=PLANE('',#878);
#880=ORIENTED_EDGE('',*,*,#697,.T.);
#881=ORIENTED_EDGE('',*,*,#175,.T.);
#882=ORIENTED_EDGE('',*,*,#525,.T.);
#883=ORIENTED_EDGE('',*,*,#98,.F.);
#884=ORIENTED_EDGE('',*,*,#353,.T.);
#885=ORIENTED_EDGE('',*,*,#140,.F.);
#886=ORIENTED_EDGE('',*,*,#869,.T.);
#887=ORIENTED_EDGE('',*,*,#49,.T.);
#888=EDGE_LOOP('',(#880,#881,#882,#883,#884,#885,#886,#887));
#889=FACE_BOUND('',#888,.T.);
#890=ADVANCED_FACE('F128',(#889),#879,.F.);
#891=CARTESIAN_POINT('',(-0.1,-9.2,0.));
#892=DIRECTION('',(-1.,0.,0.));
#893=DIRECTION('',(0.,0.,1.));
#894=AXIS2_PLACEMENT_3D('',#891,#892,#893);
#895=PLANE('',#894);
#896=ORIENTED_EDGE('',*,*,#615,.T.);
#897=ORIENTED_EDGE('',*,*,#32,.T.);
#898=ORIENTED_EDGE('',*,*,#787,.T.);
#899=ORIENTED_EDGE('',*,*,#125,.F.);
#900=ORIENTED_EDGE('',*,*,#271,.T.);
#901=ORIENTED_EDGE('',*,*,#83,.F.);
#902=ORIENTED_EDGE('',*,*,#443,.T.);
#903=ORIENTED_EDGE('',*,*,#158,.T.);
#904=EDGE_LOOP('',(#896,#897,#898,#899,#900,#901,#902,#903));
#905=FACE_BOUND('',#904,.T.);
#906=ADVANCED_FACE('F97',(#905),#895,.F.);
#907=CLOSED_SHELL('',(#60,#102,#144,#186,#358,#530,#702,#874,#890,#906));
#908=MANIFOLD_SOLID_BREP('B2',#907);
#909=ADVANCED_BREP_SHAPE_REPRESENTATION('',(#18,#908),#14);
#910=SHAPE_DEFINITION_REPRESENTATION(#9,#909);
ENDSEC;
END-ISO-10303-21;
